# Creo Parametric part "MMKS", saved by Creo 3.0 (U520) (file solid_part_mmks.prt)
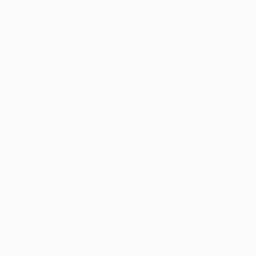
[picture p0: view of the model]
Units: millimeter Kilogram Sec (mmKs); MM, KILOGRAM, SECS

Created from: SOLID_PART_MMKS.PRT

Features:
  1. coordinate system
  2. datum plane "RIGHT"
  3. datum plane "TOP"
  4. datum plane "FRONT"

Surfaces: 3 plane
